VERSION 5.4 ;
NAMESCASESENSITIVE ON ;
BUSBITCHARS "[]" ;
DIVIDERCHAR "/" ;
UNITS
  DATABASE MICRONS 2000 ;
END UNITS
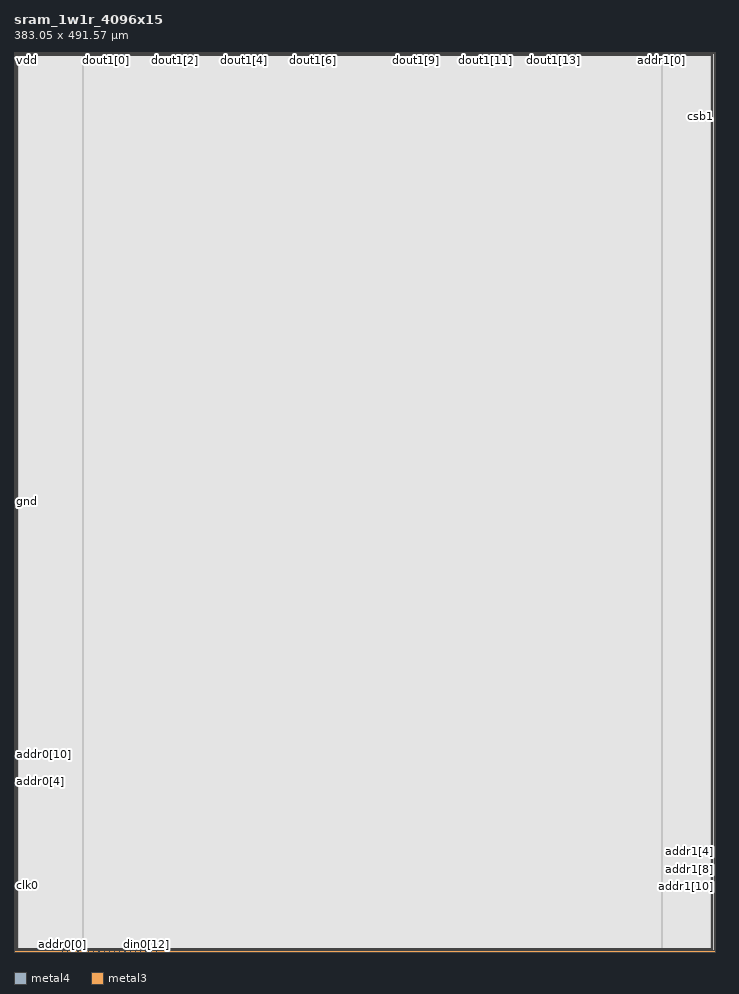
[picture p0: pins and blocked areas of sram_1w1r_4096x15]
MACRO sram_1w1r_4096x15
   CLASS BLOCK ;
   SIZE 383.05 BY 491.57 ;
   SYMMETRY X Y R90 ;
   PIN din0[0]
      DIRECTION INPUT ;
      PORT
         LAYER metal4 ;
         RECT  37.735 0.0 37.875 0.14 ;
      END
   END din0[0]
   PIN din0[1]
      DIRECTION INPUT ;
      PORT
         LAYER metal4 ;
         RECT  40.595 0.0 40.735 0.14 ;
      END
   END din0[1]
   PIN din0[2]
      DIRECTION INPUT ;
      PORT
         LAYER metal4 ;
         RECT  43.455 0.0 43.595 0.14 ;
      END
   END din0[2]
   PIN din0[3]
      DIRECTION INPUT ;
      PORT
         LAYER metal4 ;
         RECT  46.315 0.0 46.455 0.14 ;
      END
   END din0[3]
   PIN din0[4]
      DIRECTION INPUT ;
      PORT
         LAYER metal4 ;
         RECT  49.175 0.0 49.315 0.14 ;
      END
   END din0[4]
   PIN din0[5]
      DIRECTION INPUT ;
      PORT
         LAYER metal4 ;
         RECT  52.035 0.0 52.175 0.14 ;
      END
   END din0[5]
   PIN din0[6]
      DIRECTION INPUT ;
      PORT
         LAYER metal4 ;
         RECT  54.895 0.0 55.035 0.14 ;
      END
   END din0[6]
   PIN din0[7]
      DIRECTION INPUT ;
      PORT
         LAYER metal4 ;
         RECT  57.755 0.0 57.895 0.14 ;
      END
   END din0[7]
   PIN din0[8]
      DIRECTION INPUT ;
      PORT
         LAYER metal4 ;
         RECT  60.615 0.0 60.755 0.14 ;
      END
   END din0[8]
   PIN din0[9]
      DIRECTION INPUT ;
      PORT
         LAYER metal4 ;
         RECT  63.475 0.0 63.615 0.14 ;
      END
   END din0[9]
   PIN din0[10]
      DIRECTION INPUT ;
      PORT
         LAYER metal4 ;
         RECT  66.335 0.0 66.475 0.14 ;
      END
   END din0[10]
   PIN din0[11]
      DIRECTION INPUT ;
      PORT
         LAYER metal4 ;
         RECT  69.195 0.0 69.335 0.14 ;
      END
   END din0[11]
   PIN din0[12]
      DIRECTION INPUT ;
      PORT
         LAYER metal4 ;
         RECT  72.055 0.0 72.195 0.14 ;
      END
   END din0[12]
   PIN din0[13]
      DIRECTION INPUT ;
      PORT
         LAYER metal4 ;
         RECT  74.915 0.0 75.055 0.14 ;
      END
   END din0[13]
   PIN din0[14]
      DIRECTION INPUT ;
      PORT
         LAYER metal4 ;
         RECT  77.775 0.0 77.915 0.14 ;
      END
   END din0[14]
   PIN addr0[0]
      DIRECTION INPUT ;
      PORT
         LAYER metal4 ;
         RECT  26.295 0.0 26.435 0.14 ;
      END
   END addr0[0]
   PIN addr0[1]
      DIRECTION INPUT ;
      PORT
         LAYER metal4 ;
         RECT  29.155 0.0 29.295 0.14 ;
      END
   END addr0[1]
   PIN addr0[2]
      DIRECTION INPUT ;
      PORT
         LAYER metal4 ;
         RECT  32.015 0.0 32.155 0.14 ;
      END
   END addr0[2]
   PIN addr0[3]
      DIRECTION INPUT ;
      PORT
         LAYER metal4 ;
         RECT  34.875 0.0 35.015 0.14 ;
      END
   END addr0[3]
   PIN addr0[4]
      DIRECTION INPUT ;
      PORT
         LAYER metal3 ;
         RECT  0.0 93.06 0.14 93.2 ;
      END
   END addr0[4]
   PIN addr0[5]
      DIRECTION INPUT ;
      PORT
         LAYER metal3 ;
         RECT  0.0 95.79 0.14 95.93 ;
      END
   END addr0[5]
   PIN addr0[6]
      DIRECTION INPUT ;
      PORT
         LAYER metal3 ;
         RECT  0.0 98.0 0.14 98.14 ;
      END
   END addr0[6]
   PIN addr0[7]
      DIRECTION INPUT ;
      PORT
         LAYER metal3 ;
         RECT  0.0 100.73 0.14 100.87 ;
      END
   END addr0[7]
   PIN addr0[8]
      DIRECTION INPUT ;
      PORT
         LAYER metal3 ;
         RECT  0.0 102.94 0.14 103.08 ;
      END
   END addr0[8]
   PIN addr0[9]
      DIRECTION INPUT ;
      PORT
         LAYER metal3 ;
         RECT  0.0 105.67 0.14 105.81 ;
      END
   END addr0[9]
   PIN addr0[10]
      DIRECTION INPUT ;
      PORT
         LAYER metal3 ;
         RECT  0.0 107.88 0.14 108.02 ;
      END
   END addr0[10]
   PIN addr0[11]
      DIRECTION INPUT ;
      PORT
         LAYER metal3 ;
         RECT  0.0 110.61 0.14 110.75 ;
      END
   END addr0[11]
   PIN addr1[0]
      DIRECTION INPUT ;
      PORT
         LAYER metal4 ;
         RECT  353.755 491.43 353.895 491.57 ;
      END
   END addr1[0]
   PIN addr1[1]
      DIRECTION INPUT ;
      PORT
         LAYER metal4 ;
         RECT  350.895 491.43 351.035 491.57 ;
      END
   END addr1[1]
   PIN addr1[2]
      DIRECTION INPUT ;
      PORT
         LAYER metal4 ;
         RECT  348.035 491.43 348.175 491.57 ;
      END
   END addr1[2]
   PIN addr1[3]
      DIRECTION INPUT ;
      PORT
         LAYER metal4 ;
         RECT  345.175 491.43 345.315 491.57 ;
      END
   END addr1[3]
   PIN addr1[4]
      DIRECTION INPUT ;
      PORT
         LAYER metal3 ;
         RECT  382.91 54.97 383.05 55.11 ;
      END
   END addr1[4]
   PIN addr1[5]
      DIRECTION INPUT ;
      PORT
         LAYER metal3 ;
         RECT  382.91 52.24 383.05 52.38 ;
      END
   END addr1[5]
   PIN addr1[6]
      DIRECTION INPUT ;
      PORT
         LAYER metal3 ;
         RECT  382.91 50.03 383.05 50.17 ;
      END
   END addr1[6]
   PIN addr1[7]
      DIRECTION INPUT ;
      PORT
         LAYER metal3 ;
         RECT  382.91 47.3 383.05 47.44 ;
      END
   END addr1[7]
   PIN addr1[8]
      DIRECTION INPUT ;
      PORT
         LAYER metal3 ;
         RECT  382.91 45.09 383.05 45.23 ;
      END
   END addr1[8]
   PIN addr1[9]
      DIRECTION INPUT ;
      PORT
         LAYER metal3 ;
         RECT  382.91 42.36 383.05 42.5 ;
      END
   END addr1[9]
   PIN addr1[10]
      DIRECTION INPUT ;
      PORT
         LAYER metal3 ;
         RECT  382.91 40.15 383.05 40.29 ;
      END
   END addr1[10]
   PIN addr1[11]
      DIRECTION INPUT ;
      PORT
         LAYER metal3 ;
         RECT  382.91 37.42 383.05 37.56 ;
      END
   END addr1[11]
   PIN csb0
      DIRECTION INPUT ;
      PORT
         LAYER metal3 ;
         RECT  0.0 36.2 0.14 36.34 ;
      END
   END csb0
   PIN csb1
      DIRECTION INPUT ;
      PORT
         LAYER metal3 ;
         RECT  382.91 456.2 383.05 456.34 ;
      END
   END csb1
   PIN clk0
      DIRECTION INPUT ;
      PORT
         LAYER metal3 ;
         RECT  0.0 36.435 0.14 36.575 ;
      END
   END clk0
   PIN clk1
      DIRECTION INPUT ;
      PORT
         LAYER metal3 ;
         RECT  382.91 455.965 383.05 456.105 ;
      END
   END clk1
   PIN dout1[0]
      DIRECTION OUTPUT ;
      PORT
         LAYER metal4 ;
         RECT  50.385 491.43 50.525 491.57 ;
      END
   END dout1[0]
   PIN dout1[1]
      DIRECTION OUTPUT ;
      PORT
         LAYER metal4 ;
         RECT  69.185 491.43 69.325 491.57 ;
      END
   END dout1[1]
   PIN dout1[2]
      DIRECTION OUTPUT ;
      PORT
         LAYER metal4 ;
         RECT  87.985 491.43 88.125 491.57 ;
      END
   END dout1[2]
   PIN dout1[3]
      DIRECTION OUTPUT ;
      PORT
         LAYER metal4 ;
         RECT  106.785 491.43 106.925 491.57 ;
      END
   END dout1[3]
   PIN dout1[4]
      DIRECTION OUTPUT ;
      PORT
         LAYER metal4 ;
         RECT  125.585 491.43 125.725 491.57 ;
      END
   END dout1[4]
   PIN dout1[5]
      DIRECTION OUTPUT ;
      PORT
         LAYER metal4 ;
         RECT  144.385 491.43 144.525 491.57 ;
      END
   END dout1[5]
   PIN dout1[6]
      DIRECTION OUTPUT ;
      PORT
         LAYER metal4 ;
         RECT  163.185 491.43 163.325 491.57 ;
      END
   END dout1[6]
   PIN dout1[7]
      DIRECTION OUTPUT ;
      PORT
         LAYER metal4 ;
         RECT  181.985 491.43 182.125 491.57 ;
      END
   END dout1[7]
   PIN dout1[8]
      DIRECTION OUTPUT ;
      PORT
         LAYER metal4 ;
         RECT  200.785 491.43 200.925 491.57 ;
      END
   END dout1[8]
   PIN dout1[9]
      DIRECTION OUTPUT ;
      PORT
         LAYER metal4 ;
         RECT  219.585 491.43 219.725 491.57 ;
      END
   END dout1[9]
   PIN dout1[10]
      DIRECTION OUTPUT ;
      PORT
         LAYER metal4 ;
         RECT  238.385 491.43 238.525 491.57 ;
      END
   END dout1[10]
   PIN dout1[11]
      DIRECTION OUTPUT ;
      PORT
         LAYER metal4 ;
         RECT  257.185 491.43 257.325 491.57 ;
      END
   END dout1[11]
   PIN dout1[12]
      DIRECTION OUTPUT ;
      PORT
         LAYER metal4 ;
         RECT  275.985 491.43 276.125 491.57 ;
      END
   END dout1[12]
   PIN dout1[13]
      DIRECTION OUTPUT ;
      PORT
         LAYER metal4 ;
         RECT  294.785 491.43 294.925 491.57 ;
      END
   END dout1[13]
   PIN dout1[14]
      DIRECTION OUTPUT ;
      PORT
         LAYER metal4 ;
         RECT  313.585 491.43 313.725 491.57 ;
      END
   END dout1[14]
   PIN vdd
      DIRECTION INOUT ;
      USE POWER ; 
      SHAPE ABUTMENT ; 
      PORT
         LAYER metal4 ;
         RECT  0.0 0.0 0.7 491.57 ;
         LAYER metal3 ;
         RECT  0.0 0.0 383.05 0.7 ;
         LAYER metal3 ;
         RECT  0.0 490.87 383.05 491.57 ;
         LAYER metal4 ;
         RECT  382.35 0.0 383.05 491.57 ;
      END
   END vdd
   PIN gnd
      DIRECTION INOUT ;
      USE GROUND ; 
      SHAPE ABUTMENT ; 
      PORT
         LAYER metal3 ;
         RECT  1.4 489.47 381.65 490.17 ;
         LAYER metal4 ;
         RECT  1.4 1.4 2.1 490.17 ;
         LAYER metal3 ;
         RECT  1.4 1.4 381.65 2.1 ;
         LAYER metal4 ;
         RECT  380.95 1.4 381.65 490.17 ;
      END
   END gnd
   OBS
   LAYER  metal1 ;
      RECT  0.14 0.14 382.91 491.43 ;
   LAYER  metal2 ;
      RECT  0.14 0.14 382.91 491.43 ;
   LAYER  metal3 ;
      RECT  0.28 92.92 382.91 93.34 ;
      RECT  0.14 93.34 0.28 95.65 ;
      RECT  0.14 96.07 0.28 97.86 ;
      RECT  0.14 98.28 0.28 100.59 ;
      RECT  0.14 101.01 0.28 102.8 ;
      RECT  0.14 103.22 0.28 105.53 ;
      RECT  0.14 105.95 0.28 107.74 ;
      RECT  0.14 108.16 0.28 110.47 ;
      RECT  0.28 54.83 382.77 55.25 ;
      RECT  0.28 55.25 382.77 92.92 ;
      RECT  382.77 55.25 382.91 92.92 ;
      RECT  382.77 52.52 382.91 54.83 ;
      RECT  382.77 50.31 382.91 52.1 ;
      RECT  382.77 47.58 382.91 49.89 ;
      RECT  382.77 45.37 382.91 47.16 ;
      RECT  382.77 42.64 382.91 44.95 ;
      RECT  382.77 40.43 382.91 42.22 ;
      RECT  382.77 37.7 382.91 40.01 ;
      RECT  0.28 93.34 382.77 456.06 ;
      RECT  0.28 456.06 382.77 456.48 ;
      RECT  0.14 36.715 0.28 92.92 ;
      RECT  382.77 93.34 382.91 455.825 ;
      RECT  382.77 0.84 382.91 37.28 ;
      RECT  0.14 0.84 0.28 36.06 ;
      RECT  0.14 110.89 0.28 490.73 ;
      RECT  382.77 456.48 382.91 490.73 ;
      RECT  0.28 456.48 1.26 489.33 ;
      RECT  0.28 489.33 1.26 490.31 ;
      RECT  0.28 490.31 1.26 490.73 ;
      RECT  1.26 456.48 381.79 489.33 ;
      RECT  1.26 490.31 381.79 490.73 ;
      RECT  381.79 456.48 382.77 489.33 ;
      RECT  381.79 489.33 382.77 490.31 ;
      RECT  381.79 490.31 382.77 490.73 ;
      RECT  0.28 0.84 1.26 1.26 ;
      RECT  0.28 1.26 1.26 2.24 ;
      RECT  0.28 2.24 1.26 54.83 ;
      RECT  1.26 0.84 381.79 1.26 ;
      RECT  1.26 2.24 381.79 54.83 ;
      RECT  381.79 0.84 382.77 1.26 ;
      RECT  381.79 1.26 382.77 2.24 ;
      RECT  381.79 2.24 382.77 54.83 ;
   LAYER  metal4 ;
      RECT  37.455 0.42 38.155 491.43 ;
      RECT  38.155 0.14 40.315 0.42 ;
      RECT  41.015 0.14 43.175 0.42 ;
      RECT  43.875 0.14 46.035 0.42 ;
      RECT  46.735 0.14 48.895 0.42 ;
      RECT  49.595 0.14 51.755 0.42 ;
      RECT  52.455 0.14 54.615 0.42 ;
      RECT  55.315 0.14 57.475 0.42 ;
      RECT  58.175 0.14 60.335 0.42 ;
      RECT  61.035 0.14 63.195 0.42 ;
      RECT  63.895 0.14 66.055 0.42 ;
      RECT  66.755 0.14 68.915 0.42 ;
      RECT  69.615 0.14 71.775 0.42 ;
      RECT  72.475 0.14 74.635 0.42 ;
      RECT  75.335 0.14 77.495 0.42 ;
      RECT  26.715 0.14 28.875 0.42 ;
      RECT  29.575 0.14 31.735 0.42 ;
      RECT  32.435 0.14 34.595 0.42 ;
      RECT  35.295 0.14 37.455 0.42 ;
      RECT  38.155 0.42 353.475 491.15 ;
      RECT  353.475 0.42 354.175 491.15 ;
      RECT  351.315 491.15 353.475 491.43 ;
      RECT  348.455 491.15 350.615 491.43 ;
      RECT  345.595 491.15 347.755 491.43 ;
      RECT  38.155 491.15 50.105 491.43 ;
      RECT  50.805 491.15 68.905 491.43 ;
      RECT  69.605 491.15 87.705 491.43 ;
      RECT  88.405 491.15 106.505 491.43 ;
      RECT  107.205 491.15 125.305 491.43 ;
      RECT  126.005 491.15 144.105 491.43 ;
      RECT  144.805 491.15 162.905 491.43 ;
      RECT  163.605 491.15 181.705 491.43 ;
      RECT  182.405 491.15 200.505 491.43 ;
      RECT  201.205 491.15 219.305 491.43 ;
      RECT  220.005 491.15 238.105 491.43 ;
      RECT  238.805 491.15 256.905 491.43 ;
      RECT  257.605 491.15 275.705 491.43 ;
      RECT  276.405 491.15 294.505 491.43 ;
      RECT  295.205 491.15 313.305 491.43 ;
      RECT  314.005 491.15 344.895 491.43 ;
      RECT  0.98 0.14 26.015 0.42 ;
      RECT  78.195 0.14 382.07 0.42 ;
      RECT  354.175 491.15 382.07 491.43 ;
      RECT  0.98 0.42 1.12 1.12 ;
      RECT  0.98 1.12 1.12 490.45 ;
      RECT  0.98 490.45 1.12 491.43 ;
      RECT  1.12 0.42 2.38 1.12 ;
      RECT  1.12 490.45 2.38 491.43 ;
      RECT  2.38 0.42 37.455 1.12 ;
      RECT  2.38 1.12 37.455 490.45 ;
      RECT  2.38 490.45 37.455 491.43 ;
      RECT  354.175 0.42 380.67 1.12 ;
      RECT  354.175 1.12 380.67 490.45 ;
      RECT  354.175 490.45 380.67 491.15 ;
      RECT  380.67 0.42 381.93 1.12 ;
      RECT  380.67 490.45 381.93 491.15 ;
      RECT  381.93 0.42 382.07 1.12 ;
      RECT  381.93 1.12 382.07 490.45 ;
      RECT  381.93 490.45 382.07 491.15 ;
   END
END    sram_1w1r_4096x15
END    LIBRARY
